VERSION 5.8 ;
BUSBITCHARS "[]" ;
DIVIDERCHAR "/" ;

UNITS
  DATABASE MICRONS 1000 ;
END UNITS
MANUFACTURINGGRID 0.025 ;
LAYER OVERLAP
  TYPE OVERLAP ;
END OVERLAP

LAYER SEMI
  TYPE MASTERSLICE ;
END SEMI

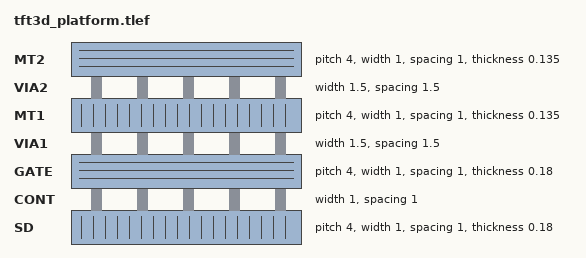
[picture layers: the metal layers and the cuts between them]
LAYER SD
  TYPE ROUTING ;
  DIRECTION VERTICAL ;
  PITCH 4 ;
  WIDTH 1 ;
  OFFSET 0 ;
  SPACING 1 ;
  SPACING 1 SAMENET ;
  MINWIDTH 1 ;
  RESISTANCE RPERSQ 0.420 ;
  CAPACITANCE CPERSQDIST 0.0001 ;
  HEIGHT 0.075 ;
  THICKNESS 0.18 ;
END SD

LAYER CONT
  TYPE CUT ;
  SPACING 1 ;
  WIDTH 1 ;
END CONT

LAYER GATE
  TYPE ROUTING ;
  DIRECTION HORIZONTAL ;
  PITCH 4 ;
  WIDTH 1 ;
  OFFSET 0 ;
  SPACING 1 ;
  SPACING 1 SAMENET ;
  MINWIDTH 1 ;
  RESISTANCE RPERSQ 0.420 ;
  CAPACITANCE CPERSQDIST 0.0001 ;
  HEIGHT 0.272 ;
  THICKNESS 0.18 ;
END GATE

LAYER VIA1
  TYPE CUT ;
  SPACING 1.5 ;
  SPACING 0.5 LAYER SD ;
  WIDTH 1.5 ;
END VIA1

LAYER MT1
  TYPE ROUTING ;
  DIRECTION VERTICAL ;
  PITCH 4 ;
  WIDTH 1 ;
  OFFSET 2 2 ;
  SPACING 1 ;
  SPACING 1 SAMENET ;
  MINWIDTH 1 ;
  RESISTANCE RPERSQ 0.420 ;
  CAPACITANCE CPERSQDIST 0.0001 ;
  HEIGHT 0.442 ;
  THICKNESS 0.135 ;
END MT1

LAYER VIA2
  TYPE CUT ;
  SPACING 1.5 ;
  SPACING 2 LAYER VIA1 ;
  WIDTH 1.5 ;
END VIA2

LAYER MT2
  TYPE ROUTING ;
  DIRECTION HORIZONTAL ;
  PITCH 4 ;
  WIDTH 1 ;
  OFFSET 2 2 ;
  SPACING 1 ;
  SPACING 1 SAMENET ;
  MINWIDTH 1 ;
  RESISTANCE RPERSQ 0.420 ;
  CAPACITANCE CPERSQDIST 0.0001 ;
  HEIGHT 0.792 ;
  THICKNESS 0.135 ;
END MT2

VIARULE SD_GATE GENERATE DEFAULT
  LAYER SD ;
    ENCLOSURE 0.5 0.5 ;
  LAYER GATE ;
    ENCLOSURE 0.5 0.5 ;
  LAYER CONT ;
    RECT -0.5 -0.5 0.5 0.5 ;
    SPACING 2 BY 2 ;
END SD_GATE

VIARULE GATE_MT1 GENERATE DEFAULT
  LAYER GATE ;
    ENCLOSURE 0.5 0.5 ;
  LAYER MT1 ;
    ENCLOSURE 0.5 0.5 ;
  LAYER VIA1 ;
    RECT -0.75 -0.75 0.75 0.75 ;
    SPACING 3 BY 3 ;
END GATE_MT1

VIARULE MT1_MT2 GENERATE DEFAULT
  LAYER MT1 ;
    ENCLOSURE 0.5 0.5 ;
  LAYER MT2 ;
    ENCLOSURE 0.5 0.5 ;
  LAYER VIA2 ;
    RECT -0.75 -0.75 0.75 0.75 ;
    SPACING 3 BY 3 ;
END MT1_MT2


VIARULE SD_GATE_STACK GENERATE DEFAULT
  LAYER SD ;
    ENCLOSURE 0.75 0.75 ;
  LAYER GATE ;
    ENCLOSURE 0.5 0.5 ;
  LAYER CONT ;
    RECT -0.5 -0.5 0.5 0.5 ;
    SPACING 3.5 BY 3.5 ;
END SD_GATE_STACK

VIARULE GATE_MT1_STACK GENERATE DEFAULT
  LAYER GATE ;
    ENCLOSURE 0.5 0.5 ;
  LAYER MT1 ;
    ENCLOSURE 0.5 0.5 ;
  LAYER VIA1 ;
    RECT -0.75 -0.75 0.75 0.75 ;
    SPACING 3.5 BY 3.5 ;
END GATE_MT1_STACK

VIARULE MT1_MT2_STACK GENERATE DEFAULT
  LAYER MT1 ;
    ENCLOSURE 0.5 0.5 ;
  LAYER MT2 ;
    ENCLOSURE 0.5 0.5 ;
  LAYER VIA2 ;
    RECT -1 -1 1 1 ;
    SPACING 3.5 BY 3.5 ;
END MT1_MT2_STACK

NONDEFAULTRULE virtuosoDefaultSetup
  HARDSPACING ;
  LAYER SD
    WIDTH 4 ;
    SPACING 1 ;
  END SD
  LAYER GATE
    WIDTH 4 ;
    SPACING 1 ;
  END GATE
  LAYER MT1
    WIDTH 4 ;
    SPACING 1 ;
  END MT1
  LAYER MT2
    WIDTH 4 ;
    SPACING 1 ;
  END MT2
  USEVIARULE SD_GATE ;
  USEVIARULE GATE_MT1 ;
  USEVIARULE MT1_MT2 ;
  USEVIARULE SD_GATE_STACK ;
  USEVIARULE GATE_MT1_STACK ;
  USEVIARULE MT1_MT2_STACK ;
END virtuosoDefaultSetup


VIA SD_GATE DEFAULT
  RESISTANCE 18 ;
  LAYER SD ;
    RECT -1.500 -1.500 1.500 1.500 ;
  LAYER CONT ;
    RECT -0.500 -0.500 0.500 0.500 ;
  LAYER GATE ;
    RECT -1.500 -1.500 1.500 1.500 ;
END SD_GATE

VIA GATE_MT1 DEFAULT
  RESISTANCE 14 ;
  LAYER GATE ;
    RECT -1.500 -1.500 1.500 1.500 ;
  LAYER VIA1 ;
    RECT -0.750 -0.750 0.750 0.750 ;
  LAYER MT1 ;
    RECT -1.500 -1.500 1.500 1.500 ;
END GATE_MT1

VIA MT1_MT2 DEFAULT
  RESISTANCE 14 ;
  LAYER MT1 ;
    RECT -1.250 -1.250 1.250 1.250 ;
  LAYER VIA2 ;
    RECT -0.750 -0.750 0.750 0.750 ;
  LAYER MT2 ;
    RECT -1.250 -1.250 1.250 1.250 ;
END MT1_MT2

#MT1 to MT2 (VIA 2) Double VIAs

VIA MT1_MT2_2CUT_E DEFAULT
  RESISTANCE 7 ;
  LAYER MT1 ;
    RECT -1.250 -1.250 4.250 1.250 ;
  LAYER VIA2 ;
    RECT -0.750 -0.750 0.750 0.750 ;
    RECT  2.250 -0.750 3.750 0.750 ;
  LAYER MT2 ;
    RECT -1.250 -1.250 4.250 1.250 ;
END MT1_MT2_2CUT_E

VIA MT1_MT2_2CUT_W DEFAULT
  RESISTANCE 7 ;
  LAYER MT1 ;
    RECT 1.250 -1.250 -4.250 1.250 ;
  LAYER VIA2 ;
    RECT -0.750 -0.750  0.750 0.750 ;
    RECT -2.250 -0.750 -3.750 0.750 ;
  LAYER MT2 ;
    RECT 1.250 -1.250 -4.250 1.250 ;
END MT1_MT2_2CUT_W


VIA MT1_MT2_2CUT_N DEFAULT
  RESISTANCE 7 ;
  LAYER MT1 ;
    RECT -1.250 -1.250 1.250 4.250 ;
  LAYER VIA2 ;
    RECT -0.750 -0.750  0.750 0.750 ;
    RECT -0.750  2.250  0.750 3.750 ;
  LAYER MT2 ;
    RECT -1.250 -1.250 1.250 4.250 ;
END MT1_MT2_2CUT_N

VIA MT1_MT2_2CUT_S DEFAULT
  RESISTANCE 7 ;
  LAYER MT1 ;
    RECT -1.250 1.250 1.250 -4.250 ;
  LAYER VIA2 ;
    RECT -0.750 -0.750 0.750  0.750 ;
    RECT -0.750 -2.250 0.750 -3.750 ;
  LAYER MT2 ;
    RECT -1.250 1.250 1.250 -4.250 ;
END MT1_MT2_2CUT_S




END LIBRARY
